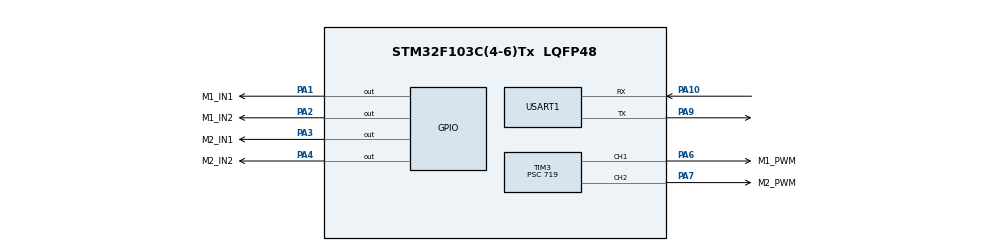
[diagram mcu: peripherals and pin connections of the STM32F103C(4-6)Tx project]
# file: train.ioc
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Mcu.Family=STM32F1
Mcu.Name=STM32F103C(4-6)Tx
Mcu.Package=LQFP48
NVIC.PriorityGroup=NVIC_PRIORITYGROUP_4
NVIC.USART1_IRQn=true\:0\:0\:false\:false\:true\:true\:true
PA1.GPIO_Label=M1_IN1
PA1.Signal=GPIO_Output
PA10.Mode=Asynchronous
PA10.Signal=USART1_RX
PA13.Mode=Serial_Wire
PA13.Signal=SYS_JTMS-SWDIO
PA14.Mode=Serial_Wire
PA14.Signal=SYS_JTCK-SWCLK
PA2.GPIO_Label=M1_IN2
PA2.Signal=GPIO_Output
PA3.GPIO_Label=M2_IN1
PA3.Signal=GPIO_Output
PA4.GPIO_Label=M2_IN2
PA4.Signal=GPIO_Output
PA6.GPIO_Label=M1_PWM
PA6.GPIO_Speed=GPIO_SPEED_FREQ_HIGH
PA6.Signal=S_TIM3_CH1
PA7.GPIO_Label=M2_PWM
PA7.GPIO_Speed=GPIO_SPEED_FREQ_HIGH
PA7.Signal=S_TIM3_CH2
PA9.Mode=Asynchronous
PA9.Signal=USART1_TX
PC14-OSC32_IN.Mode=LSE-External-Oscillator
PC14-OSC32_IN.Signal=RCC_OSC32_IN
PC15-OSC32_OUT.Mode=LSE-External-Oscillator
PC15-OSC32_OUT.Signal=RCC_OSC32_OUT
PD0-OSC_IN.Mode=HSE-External-Oscillator
PD0-OSC_IN.Signal=RCC_OSC_IN
PD1-OSC_OUT.Mode=HSE-External-Oscillator
PD1-OSC_OUT.Signal=RCC_OSC_OUT
ProjectManager.HeapSize=0x200
ProjectManager.StackSize=0x400
ProjectManager.TargetToolchain=Makefile
RCC.AHBFreq_Value=8000000
RCC.APB1CLKDivider=RCC_HCLK_DIV2
RCC.APB1Freq_Value=4000000
RCC.APB1TimFreq_Value=8000000
RCC.APB2Freq_Value=8000000
RCC.APB2TimFreq_Value=8000000
RCC.HCLKFreq_Value=8000000
RCC.PLLMUL=RCC_PLL_MUL9
RCC.PLLSourceVirtual=RCC_PLLSOURCE_HSE
RCC.SYSCLKFreq_VALUE=8000000
RCC.SYSCLKSource=RCC_SYSCLKSOURCE_HSE
RCC.USBFreq_Value=72000000
SH.S_TIM3_CH1.0=TIM3_CH1,PWM Generation1 CH1
SH.S_TIM3_CH2.0=TIM3_CH2,PWM Generation2 CH2
TIM3.Channel-PWM\ Generation1\ CH1=TIM_CHANNEL_1
TIM3.Channel-PWM\ Generation2\ CH2=TIM_CHANNEL_2
TIM3.Period=1000
TIM3.Prescaler=719
USART1.VirtualMode=VM_ASYNC
VP_RTC_VS_RTC_Activate.Mode=RTC_Enabled
VP_TIM1_VS_ClockSourceINT.Mode=Internal
VP_TIM3_VS_ClockSourceINT.Mode=Internal
board=custom

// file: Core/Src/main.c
/* USER CODE BEGIN Header */
/**
  ******************************************************************************
  * @file           : main.c
  * @brief          : Main program body
  ******************************************************************************
  * @attention
  *
  * <h2><center>&copy; Copyright (c) 2021 STMicroelectronics.
  * All rights reserved.</center></h2>
  *
  * This software component is licensed by ST under BSD 3-Clause license,
  * the "License"; You may not use this file except in compliance with the
  * License. You may obtain a copy of the License at:
  *                        opensource.org/licenses/BSD-3-Clause
  *
  ******************************************************************************
  */
/* USER CODE END Header */
#include "main.h"
#include "rtc.h"
#include "tim.h"
#include "usart.h"
#include "gpio.h"

/* USER CODE BEGIN Includes */
#include "common.h"
#include "motor.h"
/* USER CODE END Includes */

void SystemClock_Config(void);

int main(void)
{

  /* MCU Configuration--------------------------------------------------------*/

  /* Reset of all peripherals, Initializes the Flash interface and the Systick. */
  HAL_Init();

  /* Configure the system clock */
  SystemClock_Config();

  /* Initialize all configured peripherals */
  MX_GPIO_Init();
  MX_RTC_Init();
  MX_TIM1_Init();
  MX_TIM3_Init();
  MX_USART1_UART_Init();
  /* USER CODE BEGIN 2 */

  HAL_GPIO_WritePin(M1_IN1_GPIO_Port, M1_IN1_Pin, GPIO_PIN_SET);
  HAL_GPIO_WritePin(M1_IN2_GPIO_Port, M1_IN2_Pin, GPIO_PIN_RESET);
  HAL_GPIO_WritePin(M2_IN1_GPIO_Port, M2_IN1_Pin, GPIO_PIN_SET);
  HAL_GPIO_WritePin(M2_IN2_GPIO_Port, M2_IN2_Pin, GPIO_PIN_RESET);

  motorsInit();

  uint8_t str[] = "Init complete";
  debugPrint(str);

  motorSetSpeed(500, &Motor1);
  motorSetSpeed(500, &Motor2);

  /* USER CODE END 2 */

  /* Infinite loop */
  /* USER CODE BEGIN WHILE */
  while (1)
  {

    static uint16_t div = 0;

    HAL_Delay(10);

    motorsHandler();

    /* USER CODE END WHILE */

  }
}

void SystemClock_Config(void)
{
  RCC_OscInitTypeDef RCC_OscInitStruct = {0};
  RCC_ClkInitTypeDef RCC_ClkInitStruct = {0};
  RCC_PeriphCLKInitTypeDef PeriphClkInit = {0};

  /** Initializes the RCC Oscillators according to the specified parameters
  * in the RCC_OscInitTypeDef structure.
  */
  RCC_OscInitStruct.OscillatorType = RCC_OSCILLATORTYPE_LSI | RCC_OSCILLATORTYPE_HSE;
  RCC_OscInitStruct.HSEState = RCC_HSE_ON;
  RCC_OscInitStruct.HSEPredivValue = RCC_HSE_PREDIV_DIV1;
  RCC_OscInitStruct.HSIState = RCC_HSI_ON;
  RCC_OscInitStruct.LSIState = RCC_LSI_ON;
  RCC_OscInitStruct.PLL.PLLState = RCC_PLL_ON;
  RCC_OscInitStruct.PLL.PLLSource = RCC_PLLSOURCE_HSE;
  RCC_OscInitStruct.PLL.PLLMUL = RCC_PLL_MUL9;
  if (HAL_RCC_OscConfig(&RCC_OscInitStruct) != HAL_OK)
  {
    Error_Handler();
  }
  /** Initializes the CPU, AHB and APB buses clocks
  */
  RCC_ClkInitStruct.ClockType = RCC_CLOCKTYPE_HCLK | RCC_CLOCKTYPE_SYSCLK | RCC_CLOCKTYPE_PCLK1 | RCC_CLOCKTYPE_PCLK2;
  RCC_ClkInitStruct.SYSCLKSource = RCC_SYSCLKSOURCE_PLLCLK;
  RCC_ClkInitStruct.AHBCLKDivider = RCC_SYSCLK_DIV1;
  RCC_ClkInitStruct.APB1CLKDivider = RCC_HCLK_DIV2;
  RCC_ClkInitStruct.APB2CLKDivider = RCC_HCLK_DIV1;

  if (HAL_RCC_ClockConfig(&RCC_ClkInitStruct, FLASH_LATENCY_2) != HAL_OK)
  {
    Error_Handler();
  }
  PeriphClkInit.PeriphClockSelection = RCC_PERIPHCLK_RTC;
  PeriphClkInit.RTCClockSelection = RCC_RTCCLKSOURCE_LSI;
  if (HAL_RCCEx_PeriphCLKConfig(&PeriphClkInit) != HAL_OK)
  {
    Error_Handler();
  }
}

void Error_Handler(void)
{
  __disable_irq();
  while (1)
  {
  }
}

/************************ (C) COPYRIGHT STMicroelectronics *****END OF FILE****/
